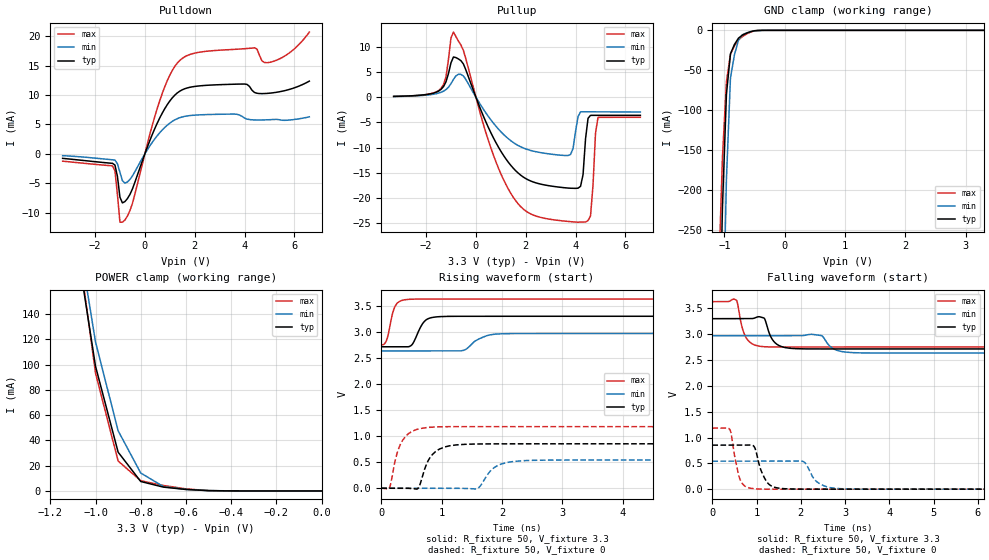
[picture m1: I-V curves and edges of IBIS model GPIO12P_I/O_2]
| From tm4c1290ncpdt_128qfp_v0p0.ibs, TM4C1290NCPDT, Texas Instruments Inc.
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|   Model Cell GPIO12P_I/O_2
[Model]   GPIO12P_I/O_2
Model_type   I/O
Polarity   Non-Inverting
Enable   Active-Low
Vinl =  0.8
Vinh =  2
Cref =  15.0000pF
Rref =  100.0000M
Vref =  0V
Vmeas =  1.65
C_comp   6.029616p   5.226915p   6.778838p
[Model Spec]
Vinl   0.8   0.8   0.8
Vinh   2   2   2
[Temperature Range]   25   125   -40
[Voltage Range]   3.3   2.97   3.63
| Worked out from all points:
|   slope of the pulldown table from 0 to 0.495 V, typ, clamps not added: 95.1 ohm
|   slope of the pullup table from 0 to 0.495 V, typ, clamps not added: 83.2 ohm
|   GND clamp passes 1 mA (typ) near -0.53 V on its own axis
|   POWER clamp passes 1 mA (typ) near -0.58 V on its own axis
|   rising waveform, R_fixture 50, V_fixture 3.3: 20-80 % time 152ps typ, 251ps min, 104ps max; typ from 2.71 V to 3.3 V
|   rising waveform, R_fixture 50, V_fixture 0: 20-80 % time 211ps typ, 246ps min, 188ps max; typ from 0 V to 0.852 V
|   falling waveform, R_fixture 50, V_fixture 3.3: 20-80 % time 194ps typ, 236ps min, 167ps max; typ from 3.3 V to 2.71 V
|   falling waveform, R_fixture 50, V_fixture 0: 20-80 % time 206ps typ, 269ps min, 156ps max; typ from 0.852 V to 0 V
| Nom Voltages:
|   IBIASFET=3.3, VDDC=1.2, VDD=3.3, GND=0
| Min Voltages:
|   IBIASFET=2.97, VDDC=1.08, VDD=2.97, GND=0
| Max Voltages:
|   IBIASFET=3.63, VDDC=1.32, VDD=3.63, GND=0
[POWER_clamp]
|   voltage   I(typ)   I(min)   I(max)
-3.3V     3.668A     4.187A     4.057A
-1.067V   175.6mA    191.7mA    181.3mA
-1.033V   137.2mA    154.7mA    137.2mA
-1V       98.66mA    117.8mA    93.17mA
-900mV    30.66mA    47.6mA     23.68mA
-800mV    7.454mA    14.17mA    8.045mA
-700mV    3.021mA    3.466mA    4.326mA
-600mV    1.166mA    1.15mA     1.613mA
-500mV    219.7uA    295.1uA    245.5uA
0V        69.07pA    1.982nA    9.028pA
[Pulldown]
|   voltage   I(typ)   I(min)   I(max)
-3.3V     -754.3uA   -301.3uA   -1.233mA
-1.3V     -1.603mA   -1.001mA   -2.021mA
-1.2V     -1.898mA   -1.04mA    -2.881mA
-1V       -7.361mA   -3.127mA   -11.61mA
-900mV    -8.329mA   -4.545mA   -11.6mA
-500mV    -5.972mA   -3.754mA   -8.422mA
700mV     6.946mA    4.079mA    10.3mA
1.4V      10.66mA    6.157mA    15.88mA
4V        11.88mA    6.091mA    17.88mA
4.4V      10.44mA    5.776mA    18.04mA
5V        10.32mA    5.812mA    15.56mA
6.6V      12.37mA    6.3mA      20.71mA
[Pullup]
|   voltage   I(typ)   I(min)   I(max)
-3.3V     147.7uA    124.8uA    136.9uA
-1.4V     1.532mA    953.4uA    1.722mA
-900mV    7.95mA     3.513mA    12.89mA
-500mV    6.556mA    4.184mA    9.232mA
1.4V      -13.51mA   -8.627mA   -19.06mA
3.9V      -18.06mA   -10.15mA   -24.71mA
4.2V      -17.67mA   -2.912mA   -24.76mA
4.5V      -4.199mA   -2.912mA   -24.45mA
4.6V      -3.612mA   -2.912mA   -23.53mA
4.8V      -3.608mA   -2.914mA   -7.146mA
4.9V      -3.607mA   -2.915mA   -4.02mA
6.6V      -3.615mA   -2.944mA   -3.997mA
[GND_clamp]
|   voltage   I(typ)   I(min)   I(max)
-3.3V     -18.01A    -17.27A    -18.6A
-1.1V     -459.9mA   -734.3mA   -318.7mA
-1.033V   -223.6mA   -411.6mA   -160.4mA
-966.7mV  -80.12mA   -186.8mA   -64.21mA
-900mV    -29.51mA   -59.8mA    -30.11mA
-833.3mV  -17.66mA   -30.4mA    -19.41mA
-766.7mV  -9.785mA   -12.28mA   -11.96mA
-700mV    -5.884mA   -5.445mA   -7.749mA
-500mV    -484.3uA   -573uA     -552.3uA
-366.7mV  -23.48uA   -48.41uA   -21.82uA
3.3V      69.07pA    6.412uA    7.794pA
[Ramp]
| variable   typ   min   max
dV/dt_f 0.37436626/0.19509738n  0.2174508/0.23873651n 0.55681925/0.1683892n
dV/dt_r  0.5218764/0.21168447n  0.3337679/0.24752585n 0.72036293/0.18845295n
R_load = 50
[Rising Waveform]
R_fixture = 50
V_fixture = 3.3
V_fixture_min = 2.97
V_fixture_max = 3.63
|   time   V(typ)   V(min)   V(max)
0s        2.714V     2.635V     2.752V
87.2ps    2.714V     2.635V     2.842V
246.5ps   2.714V     2.635V     3.527V
488ps     2.733V     2.635V     3.627V
737.6ps   3.226V     2.635V     3.63V
1.033ns   3.296V     2.635V     3.63V
1.368ns   3.299V     2.648V     3.63V
1.711ns   3.3V       2.911V     3.63V
2.101ns   3.3V       2.967V     3.63V
20.02ns   3.3V       2.97V      3.63V
[Rising Waveform]
R_fixture = 50
V_fixture = 0
V_fixture_min = 0
V_fixture_max = 0
|   time   V(typ)   V(min)   V(max)
0s        0V         0V         0V
144.1ps   0V         0V         33.28mV
244ps     0V         0V         599.9mV
352.6ps   0V         0V         918.4mV
599.5ps   -12.47mV   0V         1.131V
898.6ps   702.5mV    0V         1.176V
1.588ns   848.6mV    -8.019mV   1.182V
1.926ns   851.6mV    433.3mV    1.181V
2.476ns   852mV      534mV      1.181V
20.01ns   852.2mV    541.8mV    1.181V
[Falling Waveform]
R_fixture = 50
V_fixture = 3.3
V_fixture_min = 2.97
V_fixture_max = 3.63
|   time   V(typ)   V(min)   V(max)
0s        3.3V       2.97V      3.63V
540.5ps   3.3V       2.97V      3.658V
766.9ps   3.3V       2.97V      2.926V
1.145ns   3.319V     2.97V      2.758V
1.418ns   2.833V     2.97V      2.752V
1.869ns   2.72V      2.97V      2.752V
2.464ns   2.714V     2.974V     2.752V
2.792ns   2.714V     2.695V     2.752V
3.354ns   2.714V     2.638V     2.752V
20.02ns   2.714V     2.635V     2.752V
[Falling Waveform]
R_fixture = 50
V_fixture = 0
V_fixture_min = 0
V_fixture_max = 0
|   time   V(typ)   V(min)   V(max)
0s        852.2mV    541.8mV    1.181V
389.7ps   852.2mV    541.8mV    1.161V
645.7ps   852mV      541.8mV    149.9mV
943.2ps   826.1mV    541.8mV    8.774mV
1.074ns   430.1mV    541.8mV    0V
1.408ns   35.84mV    541.8mV    0V
2.062ns   0V         531.1mV    0V
2.404ns   0V         118mV      0V
3.008ns   0V         5.755mV    0V
20.01ns   0V         0V         0V
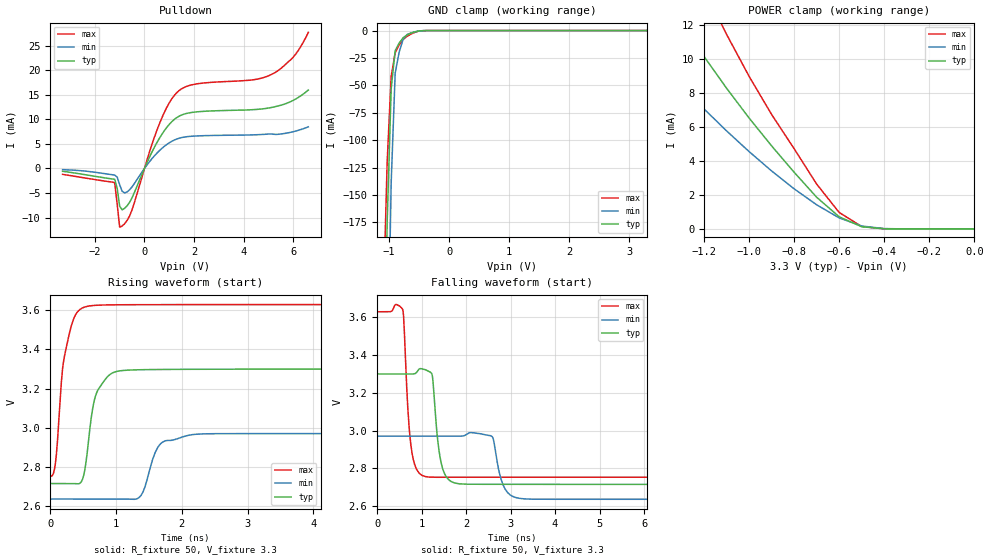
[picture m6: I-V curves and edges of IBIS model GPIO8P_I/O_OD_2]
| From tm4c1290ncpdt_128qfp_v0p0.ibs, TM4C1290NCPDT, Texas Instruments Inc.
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|   Model Cell GPIO8P_I/O_OD_2
[Model]   GPIO8P_I/O_OD_2
Model_type   I/O_open_drain
Polarity   Inverting
Enable   Active-Low
Vinl =  0.8
Vinh =  2
Cref =  15.0000pF
Rref =  100.0000M
Vref =  0V
Vmeas =  1.65
C_comp   5.378567p   4.597605p   6.118031p
[Model Spec]
Vinl   0.8   0.8   0.8
Vinh   2   2   2
[Temperature Range]   25   125   -40
[Voltage Range]   3.3   2.97   3.63
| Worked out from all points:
|   slope of the pulldown table from 0 to 0.495 V, typ, clamps not added: 95.1 ohm
|   GND clamp passes 1 mA (typ) near -0.55 V on its own axis
|   POWER clamp passes 1 mA (typ) near -0.62 V on its own axis
|   rising waveform, R_fixture 50, V_fixture 3.3: 20-80 % time 164ps typ, 198ps min, 163ps max; typ from 2.71 V to 3.3 V
|   falling waveform, R_fixture 50, V_fixture 3.3: 20-80 % time 155ps typ, 200ps min, 132ps max; typ from 3.3 V to 2.71 V
| Nom Voltages:
|   VBAT=3.3, VDDC=1.2, VDD=3.3, GND=0
| Min Voltages:
|   VBAT=2.97, VDDC=1.08, VDD=2.97, GND=0
| Max Voltages:
|   VBAT=3.63, VDDC=1.32, VDD=3.63, GND=0
[POWER_clamp]
|   voltage   I(typ)   I(min)   I(max)
-3.3V     116.1mA    496.8mA    244.3mA
-1.533V   17.14mA    11.87mA    23.97mA
-1.3V     12.14mA    8.433mA    16.92mA
-1.267V   11.48mA    7.98mA     15.99mA
-1.133V   8.919mA    6.212mA    12.36mA
-1.1V     8.296mA    5.781mA    11.47mA
-900mV    4.896mA    3.418mA    6.747mA
-800mV    3.341mA    2.365mA    4.729mA
-700mV    1.867mA    1.423mA    2.643mA
-600mV    716.2uA    650.8uA    969.8uA
-500mV    130.1uA    172.8uA    144.6uA
0V        364.7pA    9.133nA    53.42pA
[Pulldown]
|   voltage   I(typ)   I(min)   I(max)
-3.3V     -584.3uA   -253.2uA   -1.21mA
-1.2V     -2.217mA   -1.357mA   -2.921mA
-1.1V     -4.04mA    -1.763mA   -7.282mA
-1V       -7.684mA   -3.315mA   -11.97mA
-900mV    -8.442mA   -4.658mA   -11.73mA
-500mV    -5.974mA   -3.755mA   -8.425mA
600mV     6.131mA    3.613mA    9.08mA
1.3V      10.36mA    5.99mA     15.43mA
2V        11.47mA    6.588mA    17.13mA
5.1V      12.4mA     7.025mA    19.1mA
6V        13.89mA    7.492mA    22.72mA
6.6V      15.98mA    8.476mA    27.73mA
[GND_clamp]
|   voltage   I(typ)   I(min)   I(max)
-3.3V     -16.39A    -15.37A    -17.22A
-1.1V     -384.9mA   -635.5mA   -255.1mA
-1.033V   -175.3mA   -338.1mA   -120.1mA
-966.7mV  -53.11mA   -139.3mA   -41.82mA
-900mV    -18.35mA   -38.91mA   -20.36mA
-833.3mV  -11.36mA   -19.64mA   -13.17mA
-766.7mV  -6.568mA   -7.874mA   -8.128mA
-700mV    -3.981mA   -3.622mA   -5.248mA
-500mV    -326.7uA   -386.2uA   -372.4uA
-366.7mV  -15.8uA    -32.57uA   -14.68uA
3.3V      364.7pA    3.701uA    29.32pA
[Ramp]
| variable   typ   min   max
dV/dt_f 0.36846505/0.15788172n 0.21247855/0.20253052n 0.55003453/0.13382806n
dV/dt_r 0.52052121/0.19593651n 0.33112792/0.26452357n 0.72095857/0.16410135n
R_load = 50
[Rising Waveform]
R_fixture = 50
V_fixture = 3.3
V_fixture_min = 2.97
V_fixture_max = 3.63
|   time   V(typ)   V(min)   V(max)
0s        2.714V     2.635V     2.752V
81ps      2.714V     2.635V     2.826V
187.2ps   2.714V     2.635V     3.303V
284.6ps   2.714V     2.635V     3.474V
490.4ps   2.736V     2.635V     3.613V
579.8ps   2.928V     2.635V     3.622V
728.3ps   3.195V     2.635V     3.627V
1.159ns   3.294V     2.635V     3.629V
2.262ns   3.299V     2.967V     3.63V
20.03ns   3.3V       2.97V      3.63V
[Falling Waveform]
R_fixture = 50
V_fixture = 3.3
V_fixture_min = 2.97
V_fixture_max = 3.63
|   time   V(typ)   V(min)   V(max)
0s        3.3V       2.97V      3.63V
576.6ps   3.3V       2.97V      3.64V
759.4ps   3.3V       2.97V      2.921V
1.074ns   3.323V     2.97V      2.756V
1.24ns    3.291V     2.97V      2.752V
1.468ns   2.802V     2.97V      2.752V
1.847ns   2.717V     2.97V      2.752V
2.587ns   2.715V     2.967V     2.752V
3.32ns    2.714V     2.637V     2.752V
20.03ns   2.714V     2.635V     2.752V
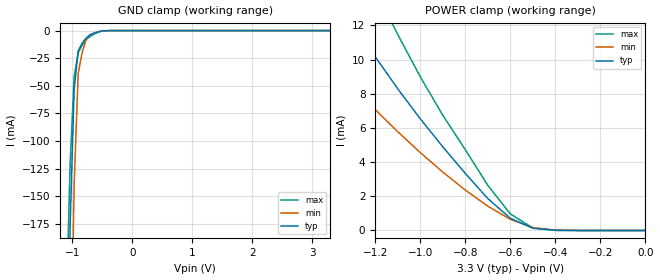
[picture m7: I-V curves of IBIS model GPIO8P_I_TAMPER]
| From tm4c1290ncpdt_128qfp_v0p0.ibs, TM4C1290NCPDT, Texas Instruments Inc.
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|   Model Cell GPIO8P_I_TAMPER
[Model]   GPIO8P_I_TAMPER
Model_type   Input
Polarity   Non-Inverting
Vinl =  0.8
Vinh =  2
C_comp   5.378567p   4.597605p   6.118031p
[Model Spec]
Vinl   0.8   0.8   0.8
Vinh   2   2   2
[Temperature Range]   25   125   -40
[Voltage Range]   3.3   2.97   3.63
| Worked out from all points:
|   GND clamp passes 1 mA (typ) near -0.55 V on its own axis
|   POWER clamp passes 1 mA (typ) near -0.62 V on its own axis
| Nom Voltages:
|   VBAT=3.3, VDDC=1.2, VDD=3.3, GND=0
| Min Voltages:
|   VBAT=2.97, VDDC=1.08, VDD=2.97, GND=0
| Max Voltages:
|   VBAT=3.63, VDDC=1.32, VDD=3.63, GND=0
[POWER_clamp]
|   voltage   I(typ)   I(min)   I(max)
-3.3V     116.1mA    496.8mA    244.3mA
-1.533V   17.14mA    11.87mA    23.97mA
-1.3V     12.14mA    8.433mA    16.92mA
-1.267V   11.48mA    7.98mA     15.99mA
-1.133V   8.919mA    6.212mA    12.36mA
-1.1V     8.296mA    5.781mA    11.47mA
-900mV    4.896mA    3.418mA    6.747mA
-800mV    3.341mA    2.365mA    4.729mA
-700mV    1.867mA    1.423mA    2.643mA
-600mV    716.2uA    650.8uA    969.8uA
-500mV    130.1uA    172.8uA    144.6uA
0V        364.7pA    9.133nA    53.42pA
[GND_clamp]
|   voltage   I(typ)   I(min)   I(max)
-3.3V     -16.39A    -15.37A    -17.22A
-1.1V     -384.9mA   -635.5mA   -255.1mA
-1.033V   -175.3mA   -338.1mA   -120.1mA
-966.7mV  -53.11mA   -139.3mA   -41.82mA
-900mV    -18.35mA   -38.91mA   -20.36mA
-833.3mV  -11.36mA   -19.64mA   -13.17mA
-766.7mV  -6.568mA   -7.874mA   -8.128mA
-700mV    -3.981mA   -3.622mA   -5.248mA
-500mV    -326.7uA   -386.2uA   -372.4uA
-366.7mV  -15.8uA    -32.57uA   -14.68uA
3.3V      364.7pA    3.701uA    29.32pA
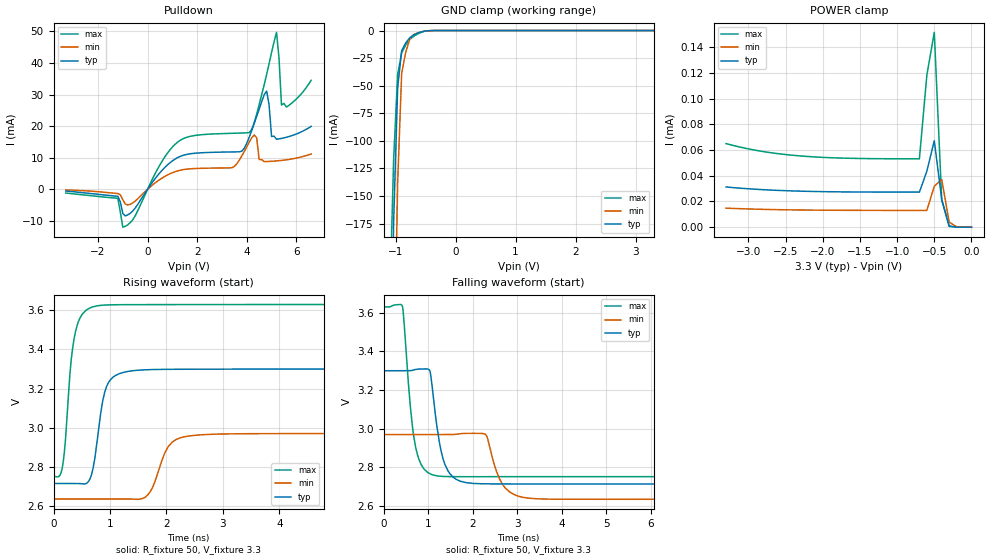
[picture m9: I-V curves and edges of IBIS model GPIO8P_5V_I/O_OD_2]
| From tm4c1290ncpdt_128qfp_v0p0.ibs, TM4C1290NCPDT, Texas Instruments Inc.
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|   Model Cell GPIO8P_5V_I/O_OD_2
[Model]   GPIO8P_5V_I/O_OD_2
Model_type   I/O_open_drain
Polarity   Inverting
Enable   Active-Low
Vinl =  0.8
Vinh =  2
Cref =  15.0000pF
Rref =  100.0000M
Vref =  0V
Vmeas =  1.65
C_comp   7.738177p   6.063161p   9.392973p
[Model Spec]
Vinl   0.8   0.8   0.8
Vinh   2   2   2
[Temperature Range]   25   125   -40
[Voltage Range]   3.3   2.97   3.63
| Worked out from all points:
|   slope of the pulldown table from 0 to 0.495 V, typ, clamps not added: 95.1 ohm
|   GND clamp passes 1 mA (typ) near -0.55 V on its own axis
|   rising waveform, R_fixture 50, V_fixture 3.3: 20-80 % time 183ps typ, 267ps min, 156ps max; typ from 2.71 V to 3.3 V
|   falling waveform, R_fixture 50, V_fixture 3.3: 20-80 % time 246ps typ, 318ps min, 212ps max; typ from 3.3 V to 2.71 V
| Nom Voltages:
|   VDDC=1.2, VDD=3.3, GND=0
| Min Voltages:
|   VDDC=1.08, VDD=2.97, GND=0
| Max Voltages:
|   VDDC=1.32, VDD=3.63, GND=0
[POWER_clamp]
|   voltage   I(typ)   I(min)   I(max)
-3.3V     31.22uA    14.77uA    64.95uA
-2.8V     29.13uA    13.84uA    58.77uA
-2.3V     27.98uA    13.34uA    55.36uA
-1.7V     27.4uA     13.1uA     53.62uA
-700mV    27.24uA    13.03uA    53.12uA
-600mV    43.52uA    13.03uA    118.2uA
-500mV    67.2uA     31.8uA     151.5uA
-400mV    21.58uA    37.04uA    21.1uA
-300mV    927.4nA    3.873uA    611.4nA
-200mV    28.93nA    266.5nA    11.51nA
0V        696.9pA    10.99nA    568.3pA
[Pulldown]
|   voltage   I(typ)   I(min)   I(max)
-3.3V     -580.7uA   -252.6uA   -1.206mA
-1.2V     -2.224mA   -1.36mA    -2.903mA
-1V       -7.701mA   -3.323mA   -12.01mA
1.2V      9.981mA    5.78mA     14.86mA
3.4V      11.82mA    6.814mA    17.72mA
4.1V      16.51mA    14.91mA    17.95mA
4.3V      20.83mA    17.22mA    21.06mA
4.8V      31.11mA    8.778mA    36.31mA
5V        16.71mA    8.862mA    43.35mA
5.2V      15.82mA    8.977mA    49.72mA
5.4V      16.11mA    9.128mA    26.68mA
6.6V      19.93mA    11.19mA    34.53mA
[GND_clamp]
|   voltage   I(typ)   I(min)   I(max)
-3.3V     -16.36A    -15.34A    -17.18A
-1.1V     -382.1mA   -633.4mA   -250.1mA
-1.033V   -173.3mA   -336.5mA   -116.4mA
-966.7mV  -52.02mA   -138.4mA   -39.81mA
-900mV    -18.21mA   -38.98mA   -20.34mA
-833.3mV  -11.36mA   -19.82mA   -13.17mA
-766.7mV  -6.618mA   -8.051mA   -8.134mA
-700mV    -3.983mA   -3.675mA   -5.247mA
-500mV    -328.3uA   -388.2uA   -374.5uA
-366.7mV  -15.94uA   -32.84uA   -14.83uA
3.3V      697pA      8.348uA    426.1pA
[Ramp]
| variable   typ   min   max
dV/dt_f 0.35736481/0.24671888n 0.20491811/0.31942174n 0.53454654/0.21282663n
dV/dt_r 0.51638227/0.48110981n 0.32917821/0.76593586n 0.71404066/0.35410299n
R_load = 50
[Rising Waveform]
R_fixture = 50
V_fixture = 3.3
V_fixture_min = 2.97
V_fixture_max = 3.63
|   time   V(typ)   V(min)   V(max)
0s        2.714V     2.635V     2.751V
173.5ps   2.714V     2.635V     2.827V
391.7ps   2.715V     2.635V     3.494V
647.3ps   2.739V     2.635V     3.612V
779.1ps   2.946V     2.635V     3.624V
975.6ps   3.232V     2.635V     3.628V
1.544ns   3.295V     2.635V     3.629V
2.099ns   3.299V     2.925V     3.63V
2.578ns   3.299V     2.963V     3.63V
20.01ns   3.3V       2.97V      3.63V
[Falling Waveform]
R_fixture = 50
V_fixture = 3.3
V_fixture_min = 2.97
V_fixture_max = 3.63
|   time   V(typ)   V(min)   V(max)
0s        3.3V       2.97V      3.63V
419.1ps   3.3V       2.97V      3.635V
714.6ps   3.307V     2.97V      2.907V
1.036ns   3.299V     2.97V      2.768V
1.18ns    3.039V     2.97V      2.757V
1.436ns   2.785V     2.97V      2.752V
1.986ns   2.717V     2.976V     2.752V
2.733ns   2.715V     2.692V     2.752V
3.263ns   2.714V     2.641V     2.752V
20.01ns   2.714V     2.635V     2.752V
